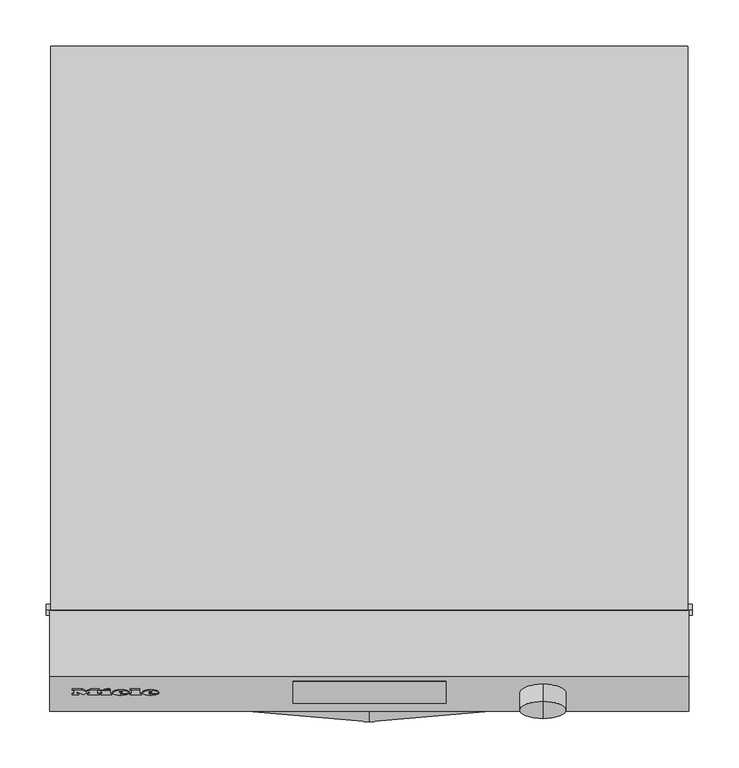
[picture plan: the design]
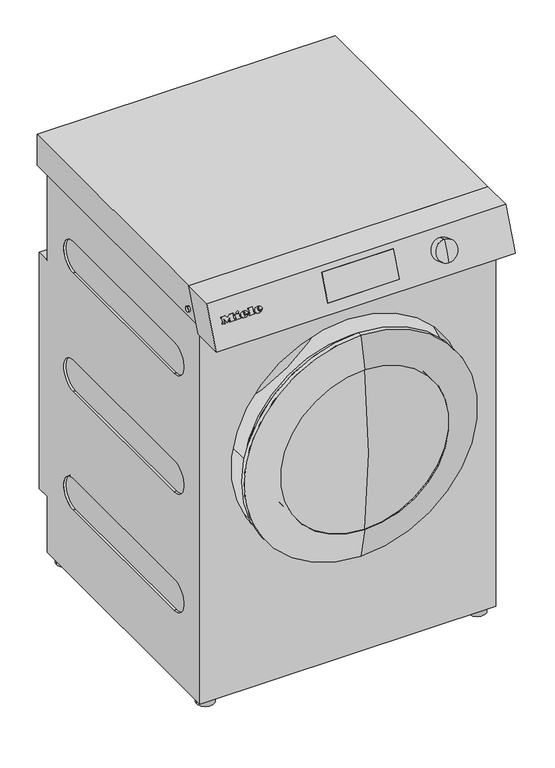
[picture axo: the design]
"""IFC4 building model written with IfcOpenShell, lengths in millimetres: proxy geometry."""

from ifc_helpers import new_model, si_unit, point, frame, frame_2d, origin, origin_with_axes, place, context, project, spatial, polyline, circle_curve, ellipse_curve, trimmed, segment, composite_curve, outline, extrude, faceted_brep, source, transform, mapped, element, save
from ifc_brep_helpers import plane_surface, cylinder_surface, revolved_surface, extruded_surface, advanced_brep


def specialty_equipment_5deedc8c(model_context):
    return source(origin(), model_context, "Body", "SolidModel", [
        advanced_brep(
        [(-238.2722, -700.6126019, 975.6957235), (-238.2722, -700.0401393, 977.1419447), (-227.9696, -700.0401393, 977.1419447), (-245.8952, -700.0401393, 977.1419447), (-241.6602, -701.9559051, 972.3021154), (-228.2314, -700.6126019, 975.6957235), (-232.8822, -700.6126019, 975.6957235), (-236.5474, -701.2474119, 974.0919931), (-238.2722, -699.3146422, 978.9747795), (-238.2722, -698.6968361, 980.5355529), (-235.6388, -698.6968361, 980.5355529), (-235.6388, -699.3146422, 978.9747795), (-238.2722, -699.6827953, 975.3276751), (-236.5474, -700.3176052, 973.7239446), (-232.8822, -699.6827953, 975.3276751), (-228.2314, -699.6827953, 975.3276751), (-241.6602, -701.0260985, 971.9340669), (-245.8952, -699.1103327, 976.7738963), (-227.9696, -699.1103327, 976.7738963), (-238.2722, -699.1103327, 976.7738963), (-238.2722, -698.3848356, 978.6067311), (-235.6388, -698.3848356, 978.6067311), (-235.6388, -697.7670295, 980.1675045), (-238.2722, -697.7670295, 980.1675045)],
        [
            (0, 1),
            (1, 2),
            (2, 3, ellipse_curve(frame((-236.9324, -700.0401393, 977.1419447), z_axis=(0.0, -0.9298066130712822, 0.36804845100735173), x_axis=(-1.0, 0.0, 0.0)), 8.9628, 7.4074)),
            (3, 4, circle_curve(frame((-239.935316, -699.8474292, 977.6287915), z_axis=(0.0, -0.9298066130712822, 0.36804845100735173), x_axis=(0.0, -0.36804845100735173, -0.9298066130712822)), 5.98284)),
            (4, 5, circle_curve(frame((-237.1118224, -698.3510914, 981.4090133), z_axis=(0.0, -0.9298066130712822, 0.36804845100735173), x_axis=(0.0, -0.36804845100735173, -0.9298066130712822)), 10.7989819)),
            (5, 6),
            (6, 7, circle_curve(frame((-235.7946118, -700.0854829, 977.0273926), z_axis=(0.0, 0.9298066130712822, -0.36804845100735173), x_axis=(0.0, -0.36804845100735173, -0.9298066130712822)), 3.2455106)),
            (7, 0, circle_curve(frame((-236.5474, -700.6126019, 975.6957235), z_axis=(0.0, 0.9298066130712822, -0.36804845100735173), x_axis=(0.0, -0.36804845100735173, -0.9298066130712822)), 1.7248)),
            (8, 9),
            (9, 10, circle_curve(frame((-236.9555, -698.6968361, 980.5355529), z_axis=(0.0, 0.9298066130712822, -0.36804845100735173), x_axis=(0.0, -0.36804845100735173, -0.9298066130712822)), 1.3167)),
            (10, 11),
            (11, 8),
            (12, 13, circle_curve(frame((-236.5474, -699.6827953, 975.3276751), z_axis=(0.0, -0.9298066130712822, 0.36804845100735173), x_axis=(0.0, -0.36804845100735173, -0.9298066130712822)), 1.7248)),
            (13, 14, circle_curve(frame((-235.7946118, -699.1556763, 976.6593441), z_axis=(0.0, -0.9298066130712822, 0.36804845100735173), x_axis=(0.0, -0.36804845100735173, -0.9298066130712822)), 3.2455106)),
            (14, 15),
            (15, 16, circle_curve(frame((-237.1118224, -697.4212848, 981.0409648), z_axis=(0.0, 0.9298066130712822, -0.36804845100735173), x_axis=(0.0, -0.36804845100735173, -0.9298066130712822)), 10.7989819)),
            (16, 17, circle_curve(frame((-239.935316, -698.9176225, 977.260743), z_axis=(0.0, 0.9298066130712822, -0.36804845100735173), x_axis=(0.0, -0.36804845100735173, -0.9298066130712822)), 5.98284)),
            (17, 18, ellipse_curve(frame((-236.9324, -699.1103327, 976.7738963), z_axis=(0.0, 0.9298066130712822, -0.36804845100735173), x_axis=(-1.0, 0.0, 0.0)), 8.9628, 7.4074)),
            (18, 19),
            (19, 12),
            (20, 21),
            (21, 22),
            (22, 23, circle_curve(frame((-236.9555, -697.7670295, 980.1675045), z_axis=(0.0, -0.9298066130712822, 0.36804845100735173), x_axis=(0.0, -0.36804845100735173, -0.9298066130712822)), 1.3167)),
            (23, 20),
            (0, 12),
            (19, 1),
            (18, 2),
            (5, 15),
            (14, 6),
            (17, 3),
            (13, 7),
            (16, 4),
            (8, 20),
            (23, 9),
            (22, 10),
            (21, 11),
        ],
        [
            plane_surface(frame((-238.2722, -700.0401393, 977.1419447), z_axis=(0.0, -0.9298066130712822, 0.36804845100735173), x_axis=(0.0, 0.36804845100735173, 0.9298066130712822))),
            plane_surface(frame((-238.2722, -699.1103327, 976.7738963), z_axis=(0.0, 0.9298066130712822, -0.36804845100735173), x_axis=(0.0, -0.36804845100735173, -0.9298066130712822))),
            plane_surface(frame((-238.2722, -700.6126019, 975.6957235), z_axis=(1.0, 0.0, 0.0), x_axis=(0.0, 0.9298066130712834, -0.3680484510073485))),
            plane_surface(frame((-238.2722, -700.0401393, 977.1419447), z_axis=(0.0, -0.3680484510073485, -0.9298066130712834), x_axis=(0.0, 0.9298066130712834, -0.3680484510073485))),
            plane_surface(frame((-228.2314, -700.6126019, 975.6957235), z_axis=(0.0, 0.3680484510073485, 0.9298066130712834), x_axis=(0.0, 0.9298066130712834, -0.3680484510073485))),
            extruded_surface(trimmed(ellipse_curve(frame((-236.9324, -698.1805261, 976.4058478), z_axis=(0.0, -0.9298066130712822, 0.36804845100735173), x_axis=(-1.0, 0.0, 0.0)), 8.9628, 7.4074), [point((-227.9696, -698.1805261, 976.4058478))], [point((-245.8952, -698.1805261, 976.4058478))], True, "CARTESIAN"), (0.0, -0.9298066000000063, 0.3680485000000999), 1.0000000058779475),
            revolved_surface(polyline([(-235.7946118, -700.3501813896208, 973.6416468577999), (-235.7946118, -701.2799880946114, 974.009695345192)]), (-235.7946118, -699.1556763, 976.6593441), (0.0, 0.9298066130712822, -0.36804845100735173)),
            revolved_surface(polyline([(-236.5474, -700.3176051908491, 973.723944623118), (-236.5474, -701.2474118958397, 974.0919931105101)]), (-236.5474, -699.6827953, 975.3276751), (0.0, 0.9298066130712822, -0.36804845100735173)),
            cylinder_surface(frame((-239.935316, -698.9176225, 977.260743), z_axis=(0.0, -0.9298066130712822, 0.36804845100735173), x_axis=(0.0, -0.36804845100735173, -0.9298066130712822)), 5.98284),
            cylinder_surface(frame((-237.1118224, -697.4212848, 981.0409648), z_axis=(0.0, -0.9298066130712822, 0.36804845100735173), x_axis=(0.0, -0.36804845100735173, -0.9298066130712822)), 10.7989819),
            plane_surface(frame((-238.2722, -699.3146422, 978.9747795), z_axis=(1.0, 0.0, 0.0), x_axis=(0.0, 0.9298066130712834, -0.3680484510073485))),
            revolved_surface(polyline([(-236.9555, -698.2516388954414, 978.943228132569), (-236.9555, -699.1814454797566, 979.3112765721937)]), (-236.9555, -697.7670295, 980.1675045), (0.0, 0.9298066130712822, -0.36804845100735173)),
            plane_surface(frame((-235.6388, -698.6968361, 980.5355529), z_axis=(-1.0, 0.0, 0.0), x_axis=(0.0, 0.9298066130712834, -0.3680484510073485))),
            plane_surface(frame((-235.6388, -699.3146422, 978.9747795), z_axis=(0.0, 0.3680484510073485, 0.9298066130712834), x_axis=(0.0, 0.9298066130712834, -0.3680484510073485))),
        ],
        [
            (0, [[1, 2, 3, 4, 5, 6, 7, 8], [9, 10, 11, 12]]),
            (1, [[13, 14, 15, 16, 17, 18, 19, 20], [21, 22, 23, 24]]),
            (2, [[-1, 25, -20, 26]]),
            (3, [[-2, -26, -19, 27]]),
            (4, [[-6, 28, -15, 29]]),
            (5, [[-3, -27, -18, 30]]),
            (6, [[-7, -29, -14, 31]]),
            (7, [[-8, -31, -13, -25]]),
            (8, [[-4, -30, -17, 32]]),
            (9, [[-5, -32, -16, -28]]),
            (10, [[-9, 33, -24, 34]]),
            (11, [[-10, -34, -23, 35]]),
            (12, [[-11, -35, -22, 36]]),
            (13, [[-12, -36, -21, -33]]),
        ],
    ),
        advanced_brep(
        [(-270.412, -700.6126019, 975.6957235), (-270.412, -700.0401393, 977.1419447), (-260.1094, -700.0401393, 977.1419447), (-278.035, -700.0401393, 977.1419447), (-273.8, -701.9559051, 972.3021154), (-260.3712, -700.6126019, 975.6957235), (-265.022, -700.6126019, 975.6957235), (-268.6872, -701.2474119, 974.0919931), (-270.412, -699.3146422, 978.9747795), (-270.412, -698.6968361, 980.5355529), (-267.7786, -698.6968361, 980.5355529), (-267.7786, -699.3146422, 978.9747795), (-270.412, -699.6827953, 975.3276751), (-268.6872, -700.3176052, 973.7239446), (-265.022, -699.6827953, 975.3276751), (-260.3712, -699.6827953, 975.3276751), (-273.8, -701.0260985, 971.9340669), (-278.035, -699.1103327, 976.7738963), (-260.1094, -699.1103327, 976.7738963), (-270.412, -699.1103327, 976.7738963), (-270.412, -698.3848356, 978.6067311), (-267.7786, -698.3848356, 978.6067311), (-267.7786, -697.7670295, 980.1675045), (-270.412, -697.7670295, 980.1675045)],
        [
            (0, 1),
            (1, 2),
            (2, 3, ellipse_curve(frame((-269.0722, -700.0401393, 977.1419447), z_axis=(0.0, -0.9298066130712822, 0.36804845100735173), x_axis=(-1.0, 0.0, 0.0)), 8.9628, 7.4074)),
            (3, 4, circle_curve(frame((-272.075116, -699.8474292, 977.6287915), z_axis=(0.0, -0.9298066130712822, 0.36804845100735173), x_axis=(0.0, -0.36804845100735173, -0.9298066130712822)), 5.98284)),
            (4, 5, circle_curve(frame((-269.2516224, -698.3510914, 981.4090133), z_axis=(0.0, -0.9298066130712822, 0.36804845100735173), x_axis=(0.0, -0.36804845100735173, -0.9298066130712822)), 10.7989819)),
            (5, 6),
            (6, 7, circle_curve(frame((-267.9344118, -700.0854829, 977.0273926), z_axis=(0.0, 0.9298066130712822, -0.36804845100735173), x_axis=(0.0, -0.36804845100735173, -0.9298066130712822)), 3.2455106)),
            (7, 0, circle_curve(frame((-268.6872, -700.6126019, 975.6957235), z_axis=(0.0, 0.9298066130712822, -0.36804845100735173), x_axis=(0.0, -0.36804845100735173, -0.9298066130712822)), 1.7248)),
            (8, 9),
            (9, 10, circle_curve(frame((-269.0953, -698.6968361, 980.5355529), z_axis=(0.0, 0.9298066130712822, -0.36804845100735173), x_axis=(0.0, -0.36804845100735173, -0.9298066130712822)), 1.3167)),
            (10, 11),
            (11, 8),
            (12, 13, circle_curve(frame((-268.6872, -699.6827953, 975.3276751), z_axis=(0.0, -0.9298066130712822, 0.36804845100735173), x_axis=(0.0, -0.36804845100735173, -0.9298066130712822)), 1.7248)),
            (13, 14, circle_curve(frame((-267.9344118, -699.1556763, 976.6593441), z_axis=(0.0, -0.9298066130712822, 0.36804845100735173), x_axis=(0.0, -0.36804845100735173, -0.9298066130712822)), 3.2455106)),
            (14, 15),
            (15, 16, circle_curve(frame((-269.2516224, -697.4212848, 981.0409648), z_axis=(0.0, 0.9298066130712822, -0.36804845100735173), x_axis=(0.0, -0.36804845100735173, -0.9298066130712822)), 10.7989819)),
            (16, 17, circle_curve(frame((-272.075116, -698.9176225, 977.260743), z_axis=(0.0, 0.9298066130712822, -0.36804845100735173), x_axis=(0.0, -0.36804845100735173, -0.9298066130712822)), 5.98284)),
            (17, 18, ellipse_curve(frame((-269.0722, -699.1103327, 976.7738963), z_axis=(0.0, 0.9298066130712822, -0.36804845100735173), x_axis=(-1.0, 0.0, 0.0)), 8.9628, 7.4074)),
            (18, 19),
            (19, 12),
            (20, 21),
            (21, 22),
            (22, 23, circle_curve(frame((-269.0953, -697.7670295, 980.1675045), z_axis=(0.0, -0.9298066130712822, 0.36804845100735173), x_axis=(0.0, -0.36804845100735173, -0.9298066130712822)), 1.3167)),
            (23, 20),
            (0, 12),
            (19, 1),
            (18, 2),
            (5, 15),
            (14, 6),
            (17, 3),
            (13, 7),
            (16, 4),
            (8, 20),
            (23, 9),
            (22, 10),
            (21, 11),
        ],
        [
            plane_surface(frame((-270.412, -700.0401393, 977.1419447), z_axis=(0.0, -0.9298066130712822, 0.36804845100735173), x_axis=(0.0, 0.36804845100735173, 0.9298066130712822))),
            plane_surface(frame((-270.412, -699.1103327, 976.7738963), z_axis=(0.0, 0.9298066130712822, -0.36804845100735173), x_axis=(0.0, -0.36804845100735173, -0.9298066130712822))),
            plane_surface(frame((-270.412, -700.6126019, 975.6957235), z_axis=(1.0, 0.0, 0.0), x_axis=(0.0, 0.9298066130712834, -0.3680484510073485))),
            plane_surface(frame((-270.412, -700.0401393, 977.1419447), z_axis=(0.0, -0.3680484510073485, -0.9298066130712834), x_axis=(0.0, 0.9298066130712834, -0.3680484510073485))),
            plane_surface(frame((-260.3712, -700.6126019, 975.6957235), z_axis=(0.0, 0.3680484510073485, 0.9298066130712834), x_axis=(0.0, 0.9298066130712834, -0.3680484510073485))),
            extruded_surface(trimmed(ellipse_curve(frame((-269.0722, -698.1805261, 976.4058478), z_axis=(0.0, -0.9298066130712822, 0.36804845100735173), x_axis=(-1.0, 0.0, 0.0)), 8.9628, 7.4074), [point((-260.1094, -698.1805261, 976.4058478))], [point((-278.035, -698.1805261, 976.4058478))], True, "CARTESIAN"), (0.0, -0.9298066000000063, 0.3680485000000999), 1.0000000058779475),
            revolved_surface(polyline([(-267.9344118, -700.3501813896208, 973.6416468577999), (-267.9344118, -701.2799880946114, 974.009695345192)]), (-267.9344118, -699.1556763, 976.6593441), (0.0, 0.9298066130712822, -0.36804845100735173)),
            revolved_surface(polyline([(-268.6872, -700.3176051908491, 973.723944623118), (-268.6872, -701.2474118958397, 974.0919931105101)]), (-268.6872, -699.6827953, 975.3276751), (0.0, 0.9298066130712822, -0.36804845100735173)),
            cylinder_surface(frame((-272.075116, -698.9176225, 977.260743), z_axis=(0.0, -0.9298066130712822, 0.36804845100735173), x_axis=(0.0, -0.36804845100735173, -0.9298066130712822)), 5.98284),
            cylinder_surface(frame((-269.2516224, -697.4212848, 981.0409648), z_axis=(0.0, -0.9298066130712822, 0.36804845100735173), x_axis=(0.0, -0.36804845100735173, -0.9298066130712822)), 10.7989819),
            plane_surface(frame((-270.412, -699.3146422, 978.9747795), z_axis=(1.0, 0.0, 0.0), x_axis=(0.0, 0.9298066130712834, -0.3680484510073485))),
            revolved_surface(polyline([(-269.0953, -698.2516388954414, 978.943228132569), (-269.0953, -699.1814454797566, 979.3112765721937)]), (-269.0953, -697.7670295, 980.1675045), (0.0, 0.9298066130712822, -0.36804845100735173)),
            plane_surface(frame((-267.7786, -698.6968361, 980.5355529), z_axis=(-1.0, 0.0, 0.0), x_axis=(0.0, 0.9298066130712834, -0.3680484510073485))),
            plane_surface(frame((-267.7786, -699.3146422, 978.9747795), z_axis=(0.0, 0.3680484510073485, 0.9298066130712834), x_axis=(0.0, 0.9298066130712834, -0.3680484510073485))),
        ],
        [
            (0, [[1, 2, 3, 4, 5, 6, 7, 8], [9, 10, 11, 12]]),
            (1, [[13, 14, 15, 16, 17, 18, 19, 20], [21, 22, 23, 24]]),
            (2, [[-1, 25, -20, 26]]),
            (3, [[-2, -26, -19, 27]]),
            (4, [[-6, 28, -15, 29]]),
            (5, [[-3, -27, -18, 30]]),
            (6, [[-7, -29, -14, 31]]),
            (7, [[-8, -31, -13, -25]]),
            (8, [[-4, -30, -17, 32]]),
            (9, [[-5, -32, -16, -28]]),
            (10, [[-9, 33, -24, 34]]),
            (11, [[-10, -34, -23, 35]]),
            (12, [[-11, -35, -22, 36]]),
            (13, [[-12, -36, -21, -33]]),
        ],
    ),
        extrude(outline(polyline([(0.0, 0.0), (-0.0209991, -5.7737091), (-2.7701549, -5.7597671), (-2.7556966, 0.0), (0.0, 0.0)])), frame((-287.2442, -695.6925612, 985.4082665), z_axis=(0.0, -0.9298066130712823, 0.3680484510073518), x_axis=(-0.4247202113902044, 0.33320333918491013, 0.8417768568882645)), (0.0, 0.0, 1.0), 1.0),
        extrude(outline(polyline([(-0.9497773, 4.6471612), (-5.3516625, -4.7358047), (-13.5635003, -0.8833376), (-14.3222205, -2.5006095), (-16.6644765, -1.4017734), (-11.5038711, 9.5984644), (-9.1616151, 8.4996283), (-9.9399574, 6.8405303), (-4.2237375, 4.1588469), (-3.4453952, 5.8179449), (-0.9497773, 4.6471612)])), frame((-287.2442, -695.6925612, 985.4082665), z_axis=(0.0, -0.9298066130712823, 0.3680484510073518), x_axis=(-0.4247202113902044, 0.33320333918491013, 0.8417768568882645)), (0.0, 0.0, 1.0), 1.0),
        extrude(outline(polyline([(0.0, 0.0), (0.0, -2.5102), (-10.5952, -2.5102), (-10.5952, 10.3026), (-12.4894, 10.3026), (-12.4894, 12.8898), (0.0, 12.8898), (0.0, 10.3026), (-1.848, 10.3026), (-1.848, 0.0), (0.0, 0.0)])), frame((-259.247, -696.2820276, 983.9190882), z_axis=(0.0, -0.9298066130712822, 0.36804845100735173), x_axis=(-1.0, 0.0, 0.0)), (0.0, 0.0, 1.0), 1.0),
        extrude(outline(polyline([(0.0, 0.0), (0.0, -2.5102), (-10.7338, -2.5102), (-15.246, 3.2648), (-19.7428, -2.5102), (-29.1214, -2.5102), (-29.1214, 0.0), (-27.1656, 0.0), (-27.1656, 10.3026), (-29.1214, 10.3026), (-29.1214, 12.8898), (-16.8322, 12.8898), (-16.8322, 10.3026), (-18.7264, 10.3026), (-18.7264, 3.7307777), (-11.8118, 12.8898), (-4.928, 3.7988752), (-4.928, 10.3026), (-6.776, 10.3026), (-6.776, 12.8898), (0.0, 12.8898), (0.0, 10.3026), (-1.8634, 10.3026), (-1.8634, 0.0), (0.0, 0.0)])), frame((-321.7402, -696.2820276, 983.9190882), z_axis=(0.0, -0.9298066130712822, 0.36804845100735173), x_axis=(-1.0, 0.0, 0.0)), (0.0, 0.0, 1.0), 1.0),
        extrude(outline(polyline([(-639.7145833, 946.7), (-711.0145833, 946.7), (-687.0666667, 1007.2), (-615.7666667, 1007.2), (-639.7145833, 946.7)])), frame((-82.85, 0.0, 0.0), z_axis=(1.0, 0.0, 0.0), x_axis=(0.0, 1.0, 0.0)), (0.0, 0.0, 1.0), 165.7),
        faceted_brep([(346.0, -610.7, 1020.0), (346.0, -682.0, 1020.0), (346.0, -720.0, 924.0), (346.0, -648.7, 924.0), (-346.0, -610.7, 1020.0), (-346.0, -648.7, 924.0), (-346.0, -720.0, 924.0), (-346.0, -682.0, 1020.0), (-82.85, -687.0666667, 1007.2), (82.85, -687.0666667, 1007.2), (82.85, -711.0145833, 946.7), (-82.85, -711.0145833, 946.7), (82.85, -615.7666667, 1007.2), (-82.85, -615.7666667, 1007.2), (-82.85, -639.7145833, 946.7), (82.85, -639.7145833, 946.7)], [[[0, 1, 2, 3]], [[4, 5, 6, 7]], [[1, 0, 4, 7]], [[2, 1, 7, 6], [8, 9, 10, 11]], [[3, 2, 6, 5]], [[0, 3, 5, 4], [12, 13, 14, 15]], [[12, 9, 8, 13]], [[13, 8, 11, 14]], [[14, 11, 10, 15]], [[9, 12, 15, 10]]]),
        advanced_brep(
        [(188.0, -727.5986435, 960.8180789), (188.0, -709.1924159, 1007.3069032), (188.0, -690.5968862, 999.9444121), (188.0, -709.0031138, 953.4555879), (188.0, -718.9636109, 984.2874103), (188.0, -699.8, 976.7)],
        [
            (0, 1, circle_curve(frame((188.0, -718.3955297, 984.0624911), z_axis=(0.0, 0.9297764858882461, -0.36812455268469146), x_axis=(0.0, 0.36812455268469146, 0.9297764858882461)), 25.0)),
            (1, 2),
            (2, 3, circle_curve(frame((188.0, -699.8, 976.7), z_axis=(0.0, -0.9297764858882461, 0.36812455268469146), x_axis=(0.0, 0.36812455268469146, 0.9297764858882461)), 25.0)),
            (3, 0),
            (1, 0, circle_curve(frame((188.0, -718.3955297, 984.0624911), z_axis=(0.0, 0.9297764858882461, -0.36812455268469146), x_axis=(0.0, 0.36812455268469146, 0.9297764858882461)), 25.0)),
            (3, 2, circle_curve(frame((188.0, -699.8, 976.7), z_axis=(0.0, -0.9297764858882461, 0.36812455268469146), x_axis=(0.0, 0.36812455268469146, 0.9297764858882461)), 25.0)),
            (4, 1),
            (0, 4),
            (2, 5),
            (5, 3),
        ],
        [
            cylinder_surface(frame((188.0, -699.8, 976.7), z_axis=(0.0, -0.9297764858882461, 0.36812455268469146), x_axis=(0.0, 0.36812455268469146, 0.9297764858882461)), 25.0),
            revolved_surface(polyline([(188.0, -709.1924159, 1007.3069032), (188.0, -718.9636109, 984.2874103)]), (188.0, -699.8, 976.7), (0.0, -0.9297764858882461, 0.36812455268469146)),
            plane_surface(frame((188.0, -699.8, 976.7), z_axis=(0.0, 0.9297764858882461, -0.36812455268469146), x_axis=(0.0, 0.36812455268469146, 0.9297764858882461))),
        ],
        [
            (0, [[1, 2, 3, 4]]),
            (0, [[5, -4, 6, -2]]),
            (1, [[7, -1, 8]]),
            (1, [[-8, -5, -7]]),
            (2, [[-3, 9, 10]]),
            (2, [[-6, -10, -9]]),
        ],
    ),
        extrude(outline(polyline([(0.0, 943.8), (-640.9, 943.8), (-610.7, 1020.0), (0.0, 1020.0), (0.0, 943.8)])), frame((-345.0, 0.0, 0.0), z_axis=(1.0, 0.0, 0.0), x_axis=(0.0, 1.0, 0.0)), (0.0, 0.0, 1.0), 690.0),
        extrude(outline(composite_curve([segment(trimmed(circle_curve(frame_2d((-610.0, 963.8)), 6.0), [point((-610.0, 957.8))], [point((-610.0, 969.8))], False, "CARTESIAN"), True, "CONTINUOUS"), segment(trimmed(circle_curve(frame_2d((-610.0, 963.8)), 6.0), [point((-610.0, 969.8))], [point((-610.0, 957.8))], False, "CARTESIAN"), True, "CONTINUOUS")], self_intersect=False)), frame((-350.0, 0.0, 0.0), z_axis=(1.0, 0.0, 0.0), x_axis=(0.0, 1.0, 0.0)), (0.0, 0.0, 1.0), 5.0),
        extrude(outline(composite_curve([segment(trimmed(circle_curve(frame_2d((-610.0, 963.8)), 6.0), [point((-610.0, 957.8))], [point((-610.0, 969.8))], False, "CARTESIAN"), True, "CONTINUOUS"), segment(trimmed(circle_curve(frame_2d((-610.0, 963.8)), 6.0), [point((-610.0, 969.8))], [point((-610.0, 957.8))], False, "CARTESIAN"), True, "CONTINUOUS")], self_intersect=False)), frame((345.0, 0.0, 0.0), z_axis=(1.0, 0.0, 0.0), x_axis=(0.0, 1.0, 0.0)), (0.0, 0.0, 1.0), 5.0),
        advanced_brep(
        [(-0.6181593, -731.0, 562.28215), (-0.6181593, -714.5357304, 758.08215), (-0.6181593, -714.5357304, 366.48215), (-0.6181593, -655.0, 366.48215), (-0.6181593, -655.0, 758.08215), (-0.6181593, -655.0, 562.28215)],
        [
            (0, 1, circle_curve(frame((-0.6181593, 441.5, 562.28215), z_axis=(-1.0, 0.0, 0.0), x_axis=(0.0, 1.0, 0.0)), 1172.5)),
            (1, 2, circle_curve(frame((-0.6181593, -714.5357304, 562.28215), z_axis=(0.0, -1.0, 0.0), x_axis=(0.0, 0.0, 1.0)), 195.8)),
            (2, 0, circle_curve(frame((-0.6181593, 441.5, 562.28215), z_axis=(-1.0, 0.0, 0.0), x_axis=(0.0, 1.0, 0.0)), 1172.5)),
            (2, 1, circle_curve(frame((-0.6181593, -714.5357304, 562.28215), z_axis=(0.0, -1.0, 0.0), x_axis=(0.0, 0.0, 1.0)), 195.8)),
            (3, 4, circle_curve(frame((-0.6181593, -655.0, 562.28215), z_axis=(0.0, 1.0, 0.0), x_axis=(0.0, 0.0, 1.0)), 195.8)),
            (4, 5),
            (5, 3),
            (4, 3, circle_curve(frame((-0.6181593, -655.0, 562.28215), z_axis=(0.0, 1.0, 0.0), x_axis=(0.0, 0.0, 1.0)), 195.8)),
            (1, 4),
            (3, 2),
        ],
        [
            revolved_surface(trimmed(ellipse_curve(frame((-0.6181593, 441.5, 562.28215), z_axis=(1.0, 0.0, 0.0), x_axis=(0.0, 1.0, 0.0)), 1172.5, 1172.5), [point((-0.6181593, -714.5357304, 758.08215))], [point((-0.6181593, -731.0, 562.28215))], True, "CARTESIAN"), (-0.6181593, -1133.7365177, 562.28215), (0.0, -1.0, 0.0)),
            plane_surface(frame((-0.6181593, -655.0, 562.28215), z_axis=(0.0, 1.0, 0.0), x_axis=(0.0, 0.0, 1.0))),
            cylinder_surface(frame((-0.6181593, -1133.7365177, 562.28215), z_axis=(0.0, -1.0, 0.0), x_axis=(0.0, 0.0, 1.0)), 195.8),
        ],
        [
            (0, [[1, 2, 3]]),
            (0, [[-3, 4, -1]]),
            (1, [[5, 6, 7]]),
            (1, [[8, -7, -6]]),
            (2, [[-2, 9, -5, 10]]),
            (2, [[-4, -10, -8, -9]]),
        ],
    ),
        advanced_brep(
        [(-0.6181593, -655.0, 327.28215), (-0.6181593, -655.0, 797.28215), (-0.6181593, -655.0, 758.08215), (-0.6181593, -655.0, 366.48215), (-0.6181593, -661.5, 315.18215), (-0.6181593, -661.5, 809.38215), (-0.6181593, -690.7, 292.28215), (-0.6181593, -690.7, 832.28215), (-0.6181593, -700.5, 292.28215), (-0.6181593, -700.5, 832.28215), (-0.6181593, -717.25, 366.48215), (-0.6181593, -717.25, 758.08215)],
        [
            (0, 1, circle_curve(frame((-0.6181593, -655.0, 562.28215), z_axis=(0.0, 1.0, 0.0), x_axis=(0.0, 0.0, 1.0)), 235.0)),
            (1, 2),
            (2, 3, circle_curve(frame((-0.6181593, -655.0, 562.28215), z_axis=(0.0, -1.0, 0.0), x_axis=(0.0, 0.0, 1.0)), 195.8)),
            (3, 0),
            (1, 0, circle_curve(frame((-0.6181593, -655.0, 562.28215), z_axis=(0.0, 1.0, 0.0), x_axis=(0.0, 0.0, 1.0)), 235.0)),
            (3, 2, circle_curve(frame((-0.6181593, -655.0, 562.28215), z_axis=(0.0, -1.0, 0.0), x_axis=(0.0, 0.0, 1.0)), 195.8)),
            (4, 5, circle_curve(frame((-0.6181593, -661.5, 562.28215), z_axis=(0.0, 1.0, 0.0), x_axis=(0.0, 0.0, 1.0)), 247.1)),
            (5, 1),
            (0, 4),
            (5, 4, circle_curve(frame((-0.6181593, -661.5, 562.28215), z_axis=(0.0, 1.0, 0.0), x_axis=(0.0, 0.0, 1.0)), 247.1)),
            (6, 7, circle_curve(frame((-0.6181593, -690.7, 562.28215), z_axis=(0.0, 1.0, 0.0), x_axis=(0.0, 0.0, 1.0)), 270.0)),
            (7, 5),
            (4, 6),
            (7, 6, circle_curve(frame((-0.6181593, -690.7, 562.28215), z_axis=(0.0, 1.0, 0.0), x_axis=(0.0, 0.0, 1.0)), 270.0)),
            (8, 9, circle_curve(frame((-0.6181593, -700.5, 562.28215), z_axis=(0.0, 1.0, 0.0), x_axis=(0.0, 0.0, 1.0)), 270.0)),
            (9, 7),
            (6, 8),
            (9, 8, circle_curve(frame((-0.6181593, -700.5, 562.28215), z_axis=(0.0, 1.0, 0.0), x_axis=(0.0, 0.0, 1.0)), 270.0)),
            (10, 11, circle_curve(frame((-0.6181593, -717.25, 562.28215), z_axis=(0.0, 1.0, 0.0), x_axis=(0.0, 0.0, 1.0)), 195.8)),
            (11, 9),
            (8, 10),
            (11, 10, circle_curve(frame((-0.6181593, -717.25, 562.28215), z_axis=(0.0, 1.0, 0.0), x_axis=(0.0, 0.0, 1.0)), 195.8)),
            (2, 11),
            (10, 3),
        ],
        [
            plane_surface(frame((-0.6181593, -655.0, 562.28215), z_axis=(0.0, 1.0, 0.0), x_axis=(0.0, 0.0, 1.0))),
            revolved_surface(polyline([(-0.6181593, -655.0, 797.28215), (-0.6181593, -661.5, 809.38215)]), (-0.6181593, -1133.7365177, 562.28215), (0.0, -1.0, 0.0)),
            revolved_surface(polyline([(-0.6181593, -661.5, 809.38215), (-0.6181593, -690.7, 832.28215)]), (-0.6181593, -1133.7365177, 562.28215), (0.0, -1.0, 0.0)),
            cylinder_surface(frame((-0.6181593, -1133.7365177, 562.28215), z_axis=(0.0, -1.0, 0.0), x_axis=(0.0, 0.0, 1.0)), 270.0),
            revolved_surface(polyline([(-0.6181593, -700.5, 832.28215), (-0.6181593, -717.25, 758.08215)]), (-0.6181593, -1133.7365177, 562.28215), (0.0, -1.0, 0.0)),
            revolved_surface(polyline([(-0.6181593, -717.25, 758.08215), (-0.6181593, -655.0, 758.08215)]), (-0.6181593, -1133.7365177, 562.28215), (0.0, -1.0, 0.0)),
        ],
        [
            (0, [[1, 2, 3, 4]]),
            (0, [[5, -4, 6, -2]]),
            (1, [[7, 8, -1, 9]]),
            (1, [[10, -9, -5, -8]]),
            (2, [[11, 12, -7, 13]]),
            (2, [[14, -13, -10, -12]]),
            (3, [[15, 16, -11, 17]]),
            (3, [[18, -17, -14, -16]]),
            (4, [[19, 20, -15, 21]]),
            (4, [[22, -21, -18, -20]]),
            (5, [[-3, 23, -19, 24]]),
            (5, [[-6, -24, -22, -23]]),
        ],
    ),
        extrude(outline(polyline([(240.6772603, -32.7), (233.3, -32.7), (233.3, -31.4442961), (239.4215564, -31.4442961), (239.4215564, -28.1480734), (233.770889, -28.1480734), (233.770889, -26.8923696), (239.4215564, -26.8923696), (239.4215564, -23.9100729), (233.456963, -23.9100729), (233.456963, -22.654369), (240.6772603, -22.654369), (240.6772603, -32.7)])), frame((0.0, 0.0, 779.0), z_axis=(0.0, 0.0, 1.0), x_axis=(1.0, 0.0, 0.0)), (0.0, 0.0, 1.0), 1.0),
        extrude(outline(polyline([(231.4164442, -32.7), (225.1379248, -32.7), (225.1379248, -31.4442961), (230.1607403, -31.4442961), (230.1607403, -22.654369), (231.4164442, -22.654369), (231.4164442, -32.7)])), frame((0.0, 0.0, 779.0), z_axis=(0.0, 0.0, 1.0), x_axis=(1.0, 0.0, 0.0)), (0.0, 0.0, 1.0), 1.0),
        extrude(outline(composite_curve([segment(trimmed(circle_curve(frame_2d((233.3, -27.7)), 7.5), [point((225.8, -27.7))], [point((240.8, -27.7))], False, "CARTESIAN"), True, "CONTINUOUS"), segment(trimmed(circle_curve(frame_2d((233.3, -27.7)), 7.5), [point((240.8, -27.7))], [point((225.8, -27.7))], False, "CARTESIAN"), True, "CONTINUOUS")], self_intersect=False)), frame((0.0, 0.0, 780.0), z_axis=(0.0, 0.0, 1.0), x_axis=(1.0, 0.0, 0.0)), (0.0, 0.0, 1.0), 30.0),
        extrude(outline(polyline([(-36.0, 810.0), (-36.0, 890.8), (-11.2, 863.0), (-11.2, 810.0), (-36.0, 810.0)])), frame((197.0, 0.0, 0.0), z_axis=(1.0, 0.0, 0.0), x_axis=(0.0, 1.0, 0.0)), (0.0, 0.0, 1.0), 76.0),
        extrude(outline(polyline([(85.0, -189.9553275), (95.045631, -193.9652413), (95.045631, -195.0345516), (85.0, -199.0420128), (85.0, -197.7151851), (88.1392597, -196.5673933), (88.1392597, -192.4274945), (85.0, -191.2797027), (85.0, -189.9553275)]), holes=[polyline([(89.3949636, -192.8885733), (89.3949636, -196.108767), (91.864678, -195.2013248), (93.7899271, -194.4974439), (92.0805021, -193.8720445), (89.3949636, -192.8885733)])]), frame((0.0, -6.0, 0.0), z_axis=(0.0, 1.0, 0.0), x_axis=(0.0, 0.0, 1.0)), (0.0, 0.0, 1.0), 1.0),
        extrude(outline(polyline([(85.0, -200.3835558), (95.045631, -200.3835558), (95.045631, -201.6392597), (86.2557039, -201.6392597), (86.2557039, -206.6620752), (85.0, -206.6620752), (85.0, -200.3835558)])), frame((0.0, -6.0, 0.0), z_axis=(0.0, 1.0, 0.0), x_axis=(0.0, 0.0, 1.0)), (0.0, 0.0, 1.0), 1.0),
        extrude(outline(composite_curve([segment(trimmed(circle_curve(frame_2d((90.0, -198.5)), 57.5), [point((32.5, -198.5))], [point((147.5, -198.5))], False, "CARTESIAN"), True, "CONTINUOUS"), segment(trimmed(circle_curve(frame_2d((90.0, -198.5)), 57.5), [point((147.5, -198.5))], [point((32.5, -198.5))], False, "CARTESIAN"), True, "CONTINUOUS")], self_intersect=False)), frame((0.0, -36.0, 0.0), z_axis=(0.0, 1.0, 0.0), x_axis=(0.0, 0.0, 1.0)), (0.0, 0.0, 1.0), 30.0),
        extrude(outline(composite_curve([segment(trimmed(circle_curve(frame_2d((-314.5, -60.1)), 20.0), [point((-334.5, -60.1))], [point((-294.5, -60.1))], False, "CARTESIAN"), True, "CONTINUOUS"), segment(trimmed(circle_curve(frame_2d((-314.5, -60.1)), 20.0), [point((-294.5, -60.1))], [point((-334.5, -60.1))], False, "CARTESIAN"), True, "CONTINUOUS")], self_intersect=False)), origin_with_axes(), (0.0, 0.0, 1.0), 18.2),
        extrude(outline(composite_curve([segment(trimmed(circle_curve(frame_2d((314.5, -60.1)), 20.0), [point((294.5, -60.1))], [point((334.5, -60.1))], False, "CARTESIAN"), True, "CONTINUOUS"), segment(trimmed(circle_curve(frame_2d((314.5, -60.1)), 20.0), [point((334.5, -60.1))], [point((294.5, -60.1))], False, "CARTESIAN"), True, "CONTINUOUS")], self_intersect=False)), origin_with_axes(), (0.0, 0.0, 1.0), 18.2),
        extrude(outline(composite_curve([segment(trimmed(circle_curve(frame_2d((314.5, -621.3)), 20.0), [point((294.5, -621.3))], [point((334.5, -621.3))], False, "CARTESIAN"), True, "CONTINUOUS"), segment(trimmed(circle_curve(frame_2d((314.5, -621.3)), 20.0), [point((334.5, -621.3))], [point((294.5, -621.3))], False, "CARTESIAN"), True, "CONTINUOUS")], self_intersect=False)), origin_with_axes(), (0.0, 0.0, 1.0), 18.2),
        extrude(outline(composite_curve([segment(trimmed(circle_curve(frame_2d((-314.5, -621.3)), 20.0), [point((-334.5, -621.3))], [point((-294.5, -621.3))], False, "CARTESIAN"), True, "CONTINUOUS"), segment(trimmed(circle_curve(frame_2d((-314.5, -621.3)), 20.0), [point((-294.5, -621.3))], [point((-334.5, -621.3))], False, "CARTESIAN"), True, "CONTINUOUS")], self_intersect=False)), origin_with_axes(), (0.0, 0.0, 1.0), 18.2),
        advanced_brep(
        [(-342.5, -648.7, 18.2), (342.5, -648.7, 18.2), (342.5, -648.7, 924.0), (-342.5, -648.7, 924.0), (0.0, -648.7, 299.8), (0.0, -648.7, 839.8), (342.5, -5.0, 733.5), (342.5, -5.0, 433.0), (149.5, -5.0, 433.0), (-80.0, -5.0, 155.0), (-342.5, -5.0, 155.0), (-342.5, -5.0, 733.5), (-151.0, -5.0, 733.5), (-151.0, -5.0, 943.8), (149.5, -5.0, 943.8), (149.5, -5.0, 733.5), (-342.5, -640.9, 943.8), (342.5, -640.9, 943.8), (342.5, -36.0, 943.8), (149.5, -36.0, 943.8), (-151.0, -36.0, 943.8), (-342.5, -36.0, 943.8), (-342.5, -36.0, 733.5), (-342.5, -36.0, 155.0), (-342.5, -36.0, 18.2), (-342.5, -141.0, 841.5708469), (-342.5, -546.0, 841.5708469), (-342.5, -546.0, 765.5708469), (-342.5, -141.0, 765.5708469), (-342.5, -141.0, 551.8), (-342.5, -546.0, 551.8), (-342.5, -546.0, 475.8), (-342.5, -141.0, 475.8), (-342.5, -141.0, 261.8), (-342.5, -546.0, 261.8), (-342.5, -546.0, 185.8), (-342.5, -141.0, 185.8), (342.5, -36.0, 18.2), (342.5, -36.0, 433.0), (342.5, -36.0, 733.5), (342.5, -548.1, 841.5708469), (342.5, -141.0, 841.5708469), (342.5, -141.0, 765.5708469), (342.5, -548.1, 765.5708469), (342.5, -548.1, 551.8), (342.5, -141.0, 551.8), (342.5, -141.0, 475.8), (342.5, -548.1, 475.8), (342.5, -548.1, 261.8), (342.5, -141.0, 261.8), (342.5, -141.0, 185.8), (342.5, -548.1, 185.8), (0.0, -74.7, 245.4), (0.0, -74.7, 569.8), (0.0, -74.7, 894.2), (0.0, -583.4, 894.2), (0.0, -583.4, 245.4), (0.0, -583.4, 839.8), (0.0, -583.4, 299.8), (-151.0, -36.0, 733.5), (149.5, -36.0, 733.5), (-80.0, -36.0, 155.0), (149.5, -36.0, 433.0), (-337.3, -141.0, 841.5708469), (-337.3, -546.0, 841.5708469), (-337.3, -141.0, 551.8), (-337.3, -546.0, 551.8), (337.3, -548.1, 551.8), (337.3, -141.0, 551.8), (337.3, -548.1, 261.8), (337.3, -141.0, 261.8), (-337.3, -141.0, 765.5708469), (-337.3, -546.0, 765.5708469), (-337.3, -141.0, 475.8), (-337.3, -546.0, 475.8), (-337.3, -546.0, 261.8), (-337.3, -141.0, 261.8), (-337.3, -141.0, 185.8), (-337.3, -546.0, 185.8), (337.3, -548.1, 841.5708469), (337.3, -548.1, 765.5708469), (337.3, -141.0, 765.5708469), (337.3, -141.0, 841.5708469), (337.3, -548.1, 475.8), (337.3, -141.0, 475.8), (337.3, -548.1, 185.8), (337.3, -141.0, 185.8)],
        [
            (0, 1),
            (1, 2),
            (2, 3),
            (3, 0),
            (4, 5, circle_curve(frame((0.0, -648.7, 569.8), z_axis=(0.0, 1.0, 0.0), x_axis=(0.0, 0.0, 1.0)), 270.0)),
            (5, 4, circle_curve(frame((0.0, -648.7, 569.8), z_axis=(0.0, 1.0, 0.0), x_axis=(0.0, 0.0, 1.0)), 270.0)),
            (6, 7),
            (7, 8),
            (8, 9),
            (9, 10),
            (10, 11),
            (11, 12),
            (12, 13),
            (13, 14),
            (14, 15),
            (15, 6),
            (16, 17),
            (17, 18),
            (18, 19),
            (19, 14),
            (13, 20),
            (20, 21),
            (21, 16),
            (3, 16),
            (21, 22),
            (22, 11),
            (10, 23),
            (23, 24),
            (24, 0),
            (25, 26),
            (26, 27, circle_curve(frame((-342.5, -546.0, 803.5708469), z_axis=(1.0, 0.0, 0.0), x_axis=(0.0, 0.0, -1.0)), 38.0)),
            (27, 28),
            (28, 25, circle_curve(frame((-342.5, -141.0, 803.5708469), z_axis=(1.0, 0.0, 0.0), x_axis=(0.0, 0.0, -1.0)), 38.0)),
            (29, 30),
            (30, 31, circle_curve(frame((-342.5, -546.0, 513.8), z_axis=(1.0, 0.0, 0.0), x_axis=(0.0, 0.0, -1.0)), 38.0)),
            (31, 32),
            (32, 29, circle_curve(frame((-342.5, -141.0, 513.8), z_axis=(1.0, 0.0, 0.0), x_axis=(0.0, 0.0, -1.0)), 38.0)),
            (33, 34),
            (34, 35, circle_curve(frame((-342.5, -546.0, 223.8), z_axis=(1.0, 0.0, 0.0), x_axis=(0.0, 0.0, -1.0)), 38.0)),
            (35, 36),
            (36, 33, circle_curve(frame((-342.5, -141.0, 223.8), z_axis=(1.0, 0.0, 0.0), x_axis=(0.0, 0.0, -1.0)), 38.0)),
            (24, 37),
            (37, 1),
            (37, 38),
            (38, 7),
            (6, 39),
            (39, 18),
            (17, 2),
            (40, 41),
            (41, 42, circle_curve(frame((342.5, -141.0, 803.5708469), z_axis=(-1.0, 0.0, 0.0), x_axis=(0.0, 0.0, -1.0)), 38.0)),
            (42, 43),
            (43, 40, circle_curve(frame((342.5, -548.1, 803.5708469), z_axis=(-1.0, 0.0, 0.0), x_axis=(0.0, 0.0, -1.0)), 38.0)),
            (44, 45),
            (45, 46, circle_curve(frame((342.5, -141.0, 513.8), z_axis=(-1.0, 0.0, 0.0), x_axis=(0.0, 0.0, -1.0)), 38.0)),
            (46, 47),
            (47, 44, circle_curve(frame((342.5, -548.1, 513.8), z_axis=(-1.0, 0.0, 0.0), x_axis=(0.0, 0.0, -1.0)), 38.0)),
            (48, 49),
            (49, 50, circle_curve(frame((342.5, -141.0, 223.8), z_axis=(-1.0, 0.0, 0.0), x_axis=(0.0, 0.0, -1.0)), 38.0)),
            (50, 51),
            (51, 48, circle_curve(frame((342.5, -548.1, 223.8), z_axis=(-1.0, 0.0, 0.0), x_axis=(0.0, 0.0, -1.0)), 38.0)),
            (52, 53),
            (53, 54),
            (54, 52, circle_curve(frame((0.0, -74.7, 569.8), z_axis=(0.0, -1.0, 0.0), x_axis=(0.0, 0.0, 1.0)), 324.4)),
            (52, 54, circle_curve(frame((0.0, -74.7, 569.8), z_axis=(0.0, -1.0, 0.0), x_axis=(0.0, 0.0, 1.0)), 324.4)),
            (54, 55),
            (55, 56, circle_curve(frame((0.0, -583.4, 569.8), z_axis=(0.0, -1.0, 0.0), x_axis=(0.0, 0.0, 1.0)), 324.4)),
            (56, 52),
            (56, 55, circle_curve(frame((0.0, -583.4, 569.8), z_axis=(0.0, -1.0, 0.0), x_axis=(0.0, 0.0, 1.0)), 324.4)),
            (55, 57),
            (57, 58, circle_curve(frame((0.0, -583.4, 569.8), z_axis=(0.0, -1.0, 0.0), x_axis=(0.0, 0.0, 1.0)), 270.0)),
            (58, 56),
            (58, 57, circle_curve(frame((0.0, -583.4, 569.8), z_axis=(0.0, -1.0, 0.0), x_axis=(0.0, 0.0, 1.0)), 270.0)),
            (57, 5),
            (4, 58),
            (59, 22),
            (20, 59),
            (39, 60),
            (60, 19),
            (23, 61),
            (61, 62),
            (62, 38),
            (59, 12),
            (60, 15),
            (62, 8),
            (61, 9),
            (63, 64),
            (64, 26),
            (25, 63),
            (65, 66),
            (66, 30),
            (29, 65),
            (67, 68),
            (68, 45),
            (44, 67),
            (69, 70),
            (70, 49),
            (48, 69),
            (63, 71, circle_curve(frame((-337.3, -141.0, 803.5708469), z_axis=(-1.0, 0.0, 0.0), x_axis=(0.0, 0.0, -1.0)), 38.0)),
            (71, 72),
            (72, 64, circle_curve(frame((-337.3, -546.0, 803.5708469), z_axis=(-1.0, 0.0, 0.0), x_axis=(0.0, 0.0, -1.0)), 38.0)),
            (65, 73, circle_curve(frame((-337.3, -141.0, 513.8), z_axis=(-1.0, 0.0, 0.0), x_axis=(0.0, 0.0, -1.0)), 38.0)),
            (73, 74),
            (74, 66, circle_curve(frame((-337.3, -546.0, 513.8), z_axis=(-1.0, 0.0, 0.0), x_axis=(0.0, 0.0, -1.0)), 38.0)),
            (75, 76),
            (76, 77, circle_curve(frame((-337.3, -141.0, 223.8), z_axis=(-1.0, 0.0, 0.0), x_axis=(0.0, 0.0, -1.0)), 38.0)),
            (77, 78),
            (78, 75, circle_curve(frame((-337.3, -546.0, 223.8), z_axis=(-1.0, 0.0, 0.0), x_axis=(0.0, 0.0, -1.0)), 38.0)),
            (28, 71),
            (27, 72),
            (32, 73),
            (31, 74),
            (75, 34),
            (33, 76),
            (36, 77),
            (35, 78),
            (79, 80, circle_curve(frame((337.3, -548.1, 803.5708469), z_axis=(1.0, 0.0, 0.0), x_axis=(0.0, 0.0, -1.0)), 38.0)),
            (80, 81),
            (81, 82, circle_curve(frame((337.3, -141.0, 803.5708469), z_axis=(1.0, 0.0, 0.0), x_axis=(0.0, 0.0, -1.0)), 38.0)),
            (82, 79),
            (67, 83, circle_curve(frame((337.3, -548.1, 513.8), z_axis=(1.0, 0.0, 0.0), x_axis=(0.0, 0.0, -1.0)), 38.0)),
            (83, 84),
            (84, 68, circle_curve(frame((337.3, -141.0, 513.8), z_axis=(1.0, 0.0, 0.0), x_axis=(0.0, 0.0, -1.0)), 38.0)),
            (69, 85, circle_curve(frame((337.3, -548.1, 223.8), z_axis=(1.0, 0.0, 0.0), x_axis=(0.0, 0.0, -1.0)), 38.0)),
            (85, 86),
            (86, 70, circle_curve(frame((337.3, -141.0, 223.8), z_axis=(1.0, 0.0, 0.0), x_axis=(0.0, 0.0, -1.0)), 38.0)),
            (82, 41),
            (40, 79),
            (81, 42),
            (80, 43),
            (84, 46),
            (83, 47),
            (86, 50),
            (85, 51),
        ],
        [
            plane_surface(frame((-342.5, -648.7, 943.8), z_axis=(0.0, -1.0, 0.0), x_axis=(-1.0, 0.0, 0.0))),
            plane_surface(frame((-342.5, -5.0, 943.8), z_axis=(0.0, 1.0, 0.0), x_axis=(1.0, 0.0, 0.0))),
            plane_surface(frame((342.5, -648.7, 943.8), z_axis=(0.0, 0.0, 1.0), x_axis=(0.0, 1.0, 0.0))),
            plane_surface(frame((-342.5, -648.7, 943.8), z_axis=(-1.0, 0.0, 0.0), x_axis=(0.0, 1.0, 0.0))),
            plane_surface(frame((-342.5, -648.7, 18.2), z_axis=(0.0, 0.0, -1.0), x_axis=(0.0, 1.0, 0.0))),
            plane_surface(frame((342.5, -648.7, 18.2), z_axis=(1.0, 0.0, 0.0), x_axis=(0.0, 1.0, 0.0))),
            plane_surface(frame((0.0, -74.7, 569.8), z_axis=(0.0, -1.0, 0.0), x_axis=(0.0, 0.0, 1.0))),
            revolved_surface(polyline([(0.0, -583.4, 894.1999999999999), (0.0, -74.70000000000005, 894.1999999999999)]), (0.0, -777.4462454, 569.8), (0.0, -1.0, 0.0)),
            plane_surface(frame((0.0, -583.4, 569.8), z_axis=(0.0, 1.0, 0.0), x_axis=(0.0, 0.0, 1.0))),
            revolved_surface(polyline([(0.0, -648.7, 839.8), (0.0, -583.4, 839.8)]), (0.0, -777.4462454, 569.8), (0.0, -1.0, 0.0)),
            plane_surface(frame((-342.5, -640.9, 943.8), z_axis=(0.0, -0.9304083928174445, 0.36652451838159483), x_axis=(1.0, 0.0, 0.0))),
            plane_surface(frame((-151.0, -36.0, 733.5), z_axis=(0.0, 1.0, 0.0), x_axis=(1.0, 0.0, 0.0))),
            plane_surface(frame((-342.5, -36.0, 733.5), z_axis=(0.0, 0.0, 1.0), x_axis=(0.0, 1.0, 0.0))),
            plane_surface(frame((-151.0, -36.0, 733.5), z_axis=(-1.0, 0.0, 0.0), x_axis=(0.0, 1.0, 0.0))),
            plane_surface(frame((149.5, -36.0, 1020.0), z_axis=(1.0, 0.0, 0.0), x_axis=(0.0, 1.0, 0.0))),
            plane_surface(frame((149.5, -36.0, 733.5), z_axis=(0.0, 0.0, 1.0), x_axis=(0.0, 1.0, 0.0))),
            plane_surface(frame((342.5, -36.0, 433.0), z_axis=(0.0, 0.0, -1.0), x_axis=(0.0, 1.0, 0.0))),
            plane_surface(frame((149.5, -36.0, 433.0), z_axis=(0.7711689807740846, 0.0, -0.636630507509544), x_axis=(0.0, 1.0, 0.0))),
            plane_surface(frame((-80.0, -36.0, 155.0), z_axis=(0.0, 0.0, -1.0), x_axis=(0.0, 1.0, 0.0))),
            plane_surface(frame((-337.3, -141.0, 841.5708469), z_axis=(0.0, 0.0, -1.0), x_axis=(-1.0, 0.0, 0.0))),
            plane_surface(frame((-337.3, -141.0, 551.8), z_axis=(0.0, 0.0, -1.0), x_axis=(-1.0, 0.0, 0.0))),
            plane_surface(frame((337.3, -548.1, 551.8), z_axis=(0.0, 0.0, -1.0), x_axis=(1.0, 0.0, 0.0))),
            plane_surface(frame((337.3, -548.1, 261.8), z_axis=(0.0, 0.0, -1.0), x_axis=(1.0, 0.0, 0.0))),
            plane_surface(frame((-337.3, -546.0, 765.5708469), z_axis=(-1.0, 0.0, 0.0), x_axis=(0.0, 1.0, 0.0))),
            revolved_surface(polyline([(-337.3, -141.0, 765.5708469), (-342.5, -141.0, 765.5708469)]), (-809.0117344, -141.0, 803.5708469), (1.0, 0.0, 0.0)),
            plane_surface(frame((-337.3, -546.0, 765.5708469), z_axis=(0.0, 0.0, 1.0), x_axis=(-1.0, 0.0, 0.0))),
            revolved_surface(polyline([(-337.29999999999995, -141.0, 475.79999999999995), (-342.5, -141.0, 475.79999999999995)]), (-1042.3, -141.0, 513.8), (1.0, 0.0, 0.0)),
            plane_surface(frame((-337.3, -546.0, 475.8), z_axis=(0.0, 0.0, 1.0), x_axis=(-1.0, 0.0, 0.0))),
            plane_surface(frame((-337.3, -141.0, 261.8), z_axis=(0.0, 0.0, -1.0), x_axis=(-1.0, 0.0, 0.0))),
            revolved_surface(polyline([(-337.29999999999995, -141.0, 185.8), (-342.5, -141.0, 185.8)]), (-1042.3, -141.0, 223.8), (1.0, 0.0, 0.0)),
            plane_surface(frame((-337.3, -546.0, 185.8), z_axis=(0.0, 0.0, 1.0), x_axis=(-1.0, 0.0, 0.0))),
            revolved_surface(polyline([(-337.3, -546.0, 765.5708469), (-342.5, -546.0, 765.5708469)]), (-809.0117344, -546.0, 803.5708469), (1.0, 0.0, 0.0)),
            revolved_surface(polyline([(-337.29999999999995, -546.0, 475.79999999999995), (-342.5, -546.0, 475.79999999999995)]), (-1042.3, -546.0, 513.8), (1.0, 0.0, 0.0)),
            revolved_surface(polyline([(-337.29999999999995, -546.0, 185.8), (-342.5, -546.0, 185.8)]), (-1042.3, -546.0, 223.8), (1.0, 0.0, 0.0)),
            plane_surface(frame((337.3, -141.0, 841.5708469), z_axis=(1.0, 0.0, 0.0), x_axis=(0.0, 1.0, 0.0))),
            plane_surface(frame((337.3, -548.1, 841.5708469), z_axis=(0.0, 0.0, -1.0), x_axis=(1.0, 0.0, 0.0))),
            revolved_surface(polyline([(337.3, -141.0, 765.5708469), (342.5, -141.0, 765.5708469)]), (809.0117344, -141.0, 803.5708469), (-1.0, 0.0, 0.0)),
            plane_surface(frame((337.3, -141.0, 765.5708469), z_axis=(0.0, 0.0, 1.0), x_axis=(1.0, 0.0, 0.0))),
            revolved_surface(polyline([(337.3, -548.1, 765.5708469), (342.5, -548.1, 765.5708469)]), (809.0117344, -548.1, 803.5708469), (-1.0, 0.0, 0.0)),
            revolved_surface(polyline([(337.29999999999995, -141.0, 475.79999999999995), (342.5, -141.0, 475.79999999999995)]), (1042.3, -141.0, 513.8), (-1.0, 0.0, 0.0)),
            plane_surface(frame((337.3, -141.0, 475.8), z_axis=(0.0, 0.0, 1.0), x_axis=(1.0, 0.0, 0.0))),
            revolved_surface(polyline([(337.29999999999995, -548.1, 475.79999999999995), (342.5, -548.1, 475.79999999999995)]), (1042.3, -548.1, 513.8), (-1.0, 0.0, 0.0)),
            revolved_surface(polyline([(337.29999999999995, -141.0, 185.8), (342.5, -141.0, 185.8)]), (1042.3, -141.0, 223.8), (-1.0, 0.0, 0.0)),
            plane_surface(frame((337.3, -141.0, 185.8), z_axis=(0.0, 0.0, 1.0), x_axis=(1.0, 0.0, 0.0))),
            revolved_surface(polyline([(337.29999999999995, -548.1, 185.8), (342.5, -548.1, 185.8)]), (1042.3, -548.1, 223.8), (-1.0, 0.0, 0.0)),
        ],
        [
            (0, [[1, 2, 3, 4], [5, 6]]),
            (1, [[7, 8, 9, 10, 11, 12, 13, 14, 15, 16]]),
            (2, [[17, 18, 19, 20, -14, 21, 22, 23]]),
            (3, [[-4, 24, -23, 25, 26, -11, 27, 28, 29], [30, 31, 32, 33], [34, 35, 36, 37], [38, 39, 40, 41]]),
            (4, [[-1, -29, 42, 43]]),
            (5, [[-2, -43, 44, 45, -7, 46, 47, -18, 48], [49, 50, 51, 52], [53, 54, 55, 56], [57, 58, 59, 60]]),
            (6, [[61, 62, 63]]),
            (6, [[-61, 64, -62]]),
            (7, [[-63, 65, 66, 67]]),
            (7, [[-64, -67, 68, -65]]),
            (8, [[-66, 69, 70, 71]]),
            (8, [[-68, -71, 72, -69]]),
            (9, [[-70, 73, -5, 74]]),
            (9, [[-72, -74, -6, -73]]),
            (10, [[-3, -48, -17, -24]]),
            (11, [[75, -25, -22, 76]]),
            (11, [[77, 78, -19, -47]]),
            (11, [[79, 80, 81, -44, -42, -28]]),
            (12, [[-75, 82, -12, -26]]),
            (13, [[-76, -21, -13, -82]]),
            (14, [[-78, 83, -15, -20]]),
            (15, [[-77, -46, -16, -83]]),
            (16, [[-81, 84, -8, -45]]),
            (17, [[-80, 85, -9, -84]]),
            (18, [[-79, -27, -10, -85]]),
            (19, [[86, 87, -30, 88]]),
            (20, [[89, 90, -34, 91]]),
            (21, [[92, 93, -53, 94]]),
            (22, [[95, 96, -57, 97]]),
            (23, [[-86, 98, 99, 100]]),
            (23, [[-89, 101, 102, 103]]),
            (23, [[104, 105, 106, 107]]),
            (24, [[-98, -88, -33, 108]]),
            (25, [[-99, -108, -32, 109]]),
            (26, [[-101, -91, -37, 110]]),
            (27, [[-102, -110, -36, 111]]),
            (28, [[-104, 112, -38, 113]]),
            (29, [[-105, -113, -41, 114]]),
            (30, [[-106, -114, -40, 115]]),
            (31, [[-100, -109, -31, -87]]),
            (32, [[-103, -111, -35, -90]]),
            (33, [[-107, -115, -39, -112]]),
            (34, [[116, 117, 118, 119]]),
            (34, [[120, 121, 122, -92]]),
            (34, [[123, 124, 125, -95]]),
            (35, [[-119, 126, -49, 127]]),
            (36, [[-118, 128, -50, -126]]),
            (37, [[-117, 129, -51, -128]]),
            (38, [[-116, -127, -52, -129]]),
            (39, [[-122, 130, -54, -93]]),
            (40, [[-121, 131, -55, -130]]),
            (41, [[-120, -94, -56, -131]]),
            (42, [[-125, 132, -58, -96]]),
            (43, [[-124, 133, -59, -132]]),
            (44, [[-123, -97, -60, -133]]),
        ],
    ),
    ])


if __name__ == "__main__":
    model = new_model("IFC4")
    model_context = context("Model", 3, world=origin())
    ifc_project = project(units=[si_unit("LENGTHUNIT", "METRE", prefix="MILLI")], contexts=[model_context])
    site = spatial("IfcSite", under=ifc_project)
    building = spatial("IfcBuilding", under=site)
    placement = place(None, origin())
    specialty_equipment_shape = specialty_equipment_5deedc8c(model_context)
    element("IfcBuildingElementProxy", 1, Name="Specialty Equipment", at=placement, inside=building, context=model_context, shape_type="MappedRepresentation", body=[
        mapped(specialty_equipment_shape, transform((0.0, 0.0, 0.0), x_axis=(1.0, 0.0, 0.0), y_axis=(0.0, 1.0, 0.0), z_axis=(0.0, 0.0, 1.0))),
    ])
    save(model, "model.ifc")
